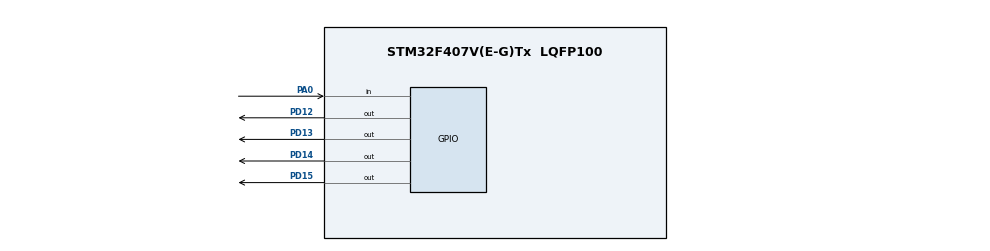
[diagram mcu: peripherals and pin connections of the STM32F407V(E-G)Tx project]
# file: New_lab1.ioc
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Mcu.Family=STM32F4
Mcu.Name=STM32F407V(E-G)Tx
Mcu.Package=LQFP100
NVIC.PriorityGroup=NVIC_PRIORITYGROUP_4
PA0-WKUP.Signal=GPIO_Input
PA13.Mode=Serial_Wire
PA13.Signal=SYS_JTMS-SWDIO
PA14.Mode=Serial_Wire
PA14.Signal=SYS_JTCK-SWCLK
PD12.Signal=GPIO_Output
PD13.Signal=GPIO_Output
PD14.Signal=GPIO_Output
PD15.Signal=GPIO_Output
PH0-OSC_IN.Mode=HSE-External-Oscillator
PH0-OSC_IN.Signal=RCC_OSC_IN
PH1-OSC_OUT.Mode=HSE-External-Oscillator
PH1-OSC_OUT.Signal=RCC_OSC_OUT
ProjectManager.HeapSize=0x200
ProjectManager.StackSize=0x400
ProjectManager.TargetToolchain=STM32CubeIDE
RCC.48MHZClocksFreq_Value=42000000
RCC.AHBFreq_Value=84000000
RCC.APB1CLKDivider=RCC_HCLK_DIV2
RCC.APB1Freq_Value=42000000
RCC.APB1TimFreq_Value=84000000
RCC.APB2Freq_Value=84000000
RCC.APB2TimFreq_Value=84000000
RCC.CortexFreq_Value=84000000
RCC.HCLKFreq_Value=84000000
RCC.HSE_VALUE=8000000
RCC.HSI_VALUE=16000000
RCC.LSE_VALUE=32768
RCC.PLLM=4
RCC.PLLN=84
RCC.PLLSourceVirtual=RCC_PLLSOURCE_HSE
RCC.SYSCLKFreq_VALUE=84000000
RCC.SYSCLKSource=RCC_SYSCLKSOURCE_PLLCLK
RCC.VCOOutputFreq_Value=168000000
board=custom

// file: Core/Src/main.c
/* USER CODE BEGIN Header */
/**
  ******************************************************************************
  * @file           : main.c
  * @brief          : Main program body
  ******************************************************************************
  * @attention
  *
  * Copyright (c) 2024 STMicroelectronics.
  * All rights reserved.
  *
  * This software is licensed under terms that can be found in the LICENSE file
  * in the root directory of this software component.
  * If no LICENSE file comes with this software, it is provided AS-IS.
  *
  ******************************************************************************
  */
/* USER CODE END Header */
#include "main.h"

/* USER CODE BEGIN PV */
uint8_t button_state = 0;
int clockwise = 1; // Flag to track the lighting direction
int mode = 0; // Variable to track the mode (frequency)
/* USER CODE END PV */

void SystemClock_Config(void);
void MX_GPIO_Init(void);

int main(void)
{
  /* MCU Configuration--------------------------------------------------------*/
  HAL_Init();
  SystemClock_Config();
  MX_GPIO_Init();

  while (1)
  {
      if (HAL_GPIO_ReadPin(GPIOA, GPIO_PIN_0) == GPIO_PIN_SET) {
          button_state = 1;
      } else {
          button_state = 0;
      }

      if (button_state == 1) {
          mode = (mode + 1) % 3;
          HAL_Delay(100);
      }

      int delay_ms = 500;
      if (mode == 1) {
          delay_ms = 250;
      } else if (mode == 2) {
          delay_ms = 100;
      }

      if (clockwise) {
          for(int i = 12; i <= 15; i++) {
              HAL_GPIO_TogglePin(GPIOD, (1 << i));
              HAL_Delay(delay_ms);
              HAL_GPIO_TogglePin(GPIOD, (1 << i));
          }
      } else {
          for(int i = 15; i >= 12; i--) {
              HAL_GPIO_TogglePin(GPIOD, (1 << i));
              HAL_Delay(delay_ms);
              HAL_GPIO_TogglePin(GPIOD, (1 << i));
          }
      }
  }
}

void SystemClock_Config(void)
{
  RCC_OscInitTypeDef RCC_OscInitStruct = {0};
  RCC_ClkInitTypeDef RCC_ClkInitStruct = {0};

  /** Configure the main internal regulator output voltage
  */
  __HAL_RCC_PWR_CLK_ENABLE();
  __HAL_PWR_VOLTAGESCALING_CONFIG(PWR_REGULATOR_VOLTAGE_SCALE1);

  /** Initializes the RCC Oscillators according to the specified parameters
  * in the RCC_OscInitTypeDef structure.
  */
  RCC_OscInitStruct.OscillatorType = RCC_OSCILLATORTYPE_HSE;
  RCC_OscInitStruct.HSEState = RCC_HSE_ON;
  RCC_OscInitStruct.PLL.PLLState = RCC_PLL_ON;
  RCC_OscInitStruct.PLL.PLLSource = RCC_PLLSOURCE_HSE;
  RCC_OscInitStruct.PLL.PLLM = 4;
  RCC_OscInitStruct.PLL.PLLN = 84;
  RCC_OscInitStruct.PLL.PLLP = RCC_PLLP_DIV2;
  RCC_OscInitStruct.PLL.PLLQ = 4;
  if (HAL_RCC_OscConfig(&RCC_OscInitStruct) != HAL_OK)
  {
    Error_Handler();
  }

  /** Initializes the CPU, AHB and APB buses clocks
  */
  RCC_ClkInitStruct.ClockType = RCC_CLOCKTYPE_HCLK|RCC_CLOCKTYPE_SYSCLK
                              |RCC_CLOCKTYPE_PCLK1|RCC_CLOCKTYPE_PCLK2;
  RCC_ClkInitStruct.SYSCLKSource = RCC_SYSCLKSOURCE_PLLCLK;
  RCC_ClkInitStruct.AHBCLKDivider = RCC_SYSCLK_DIV1;
  RCC_ClkInitStruct.APB1CLKDivider = RCC_HCLK_DIV2;
  RCC_ClkInitStruct.APB2CLKDivider = RCC_HCLK_DIV2;

  if (HAL_RCC_ClockConfig(&RCC_ClkInitStruct, FLASH_LATENCY_2) != HAL_OK)
  {
    Error_Handler();
  }
}

void MX_GPIO_Init(void)
{
  GPIO_InitTypeDef GPIO_InitStruct = {0};

  /* GPIO Ports Clock Enable */
  __HAL_RCC_GPIOH_CLK_ENABLE();
  __HAL_RCC_GPIOA_CLK_ENABLE();
  __HAL_RCC_GPIOD_CLK_ENABLE();

  /*Configure GPIO pin Output Level */
  HAL_GPIO_WritePin(GPIOD, GPIO_PIN_12|GPIO_PIN_13|GPIO_PIN_14|GPIO_PIN_15, GPIO_PIN_RESET);

  /*Configure GPIO pins : PA0 */
  GPIO_InitStruct.Pin = GPIO_PIN_0;
  GPIO_InitStruct.Mode = GPIO_MODE_INPUT;
  GPIO_InitStruct.Pull = GPIO_NOPULL;
  HAL_GPIO_Init(GPIOA, &GPIO_InitStruct);

  /*Configure GPIO pins : PD12 PD13 PD14 PD15 */
  GPIO_InitStruct.Pin = GPIO_PIN_12|GPIO_PIN_13|GPIO_PIN_14|GPIO_PIN_15;
  GPIO_InitStruct.Mode = GPIO_MODE_OUTPUT_PP;
  GPIO_InitStruct.Pull = GPIO_NOPULL;
  GPIO_InitStruct.Speed = GPIO_SPEED_FREQ_LOW;
  HAL_GPIO_Init(GPIOD, &GPIO_InitStruct);
}

void Error_Handler(void)
{
  /* User can add his own implementation to report the HAL error return state */
  __disable_irq();
  while (1)
  {
  }
}
